VERSION 5.8 ;
BUSBITCHARS "[]" ;
DIVIDERCHAR "/" ;
UNITS
    DATABASE MICRONS 1000 ;
END UNITS

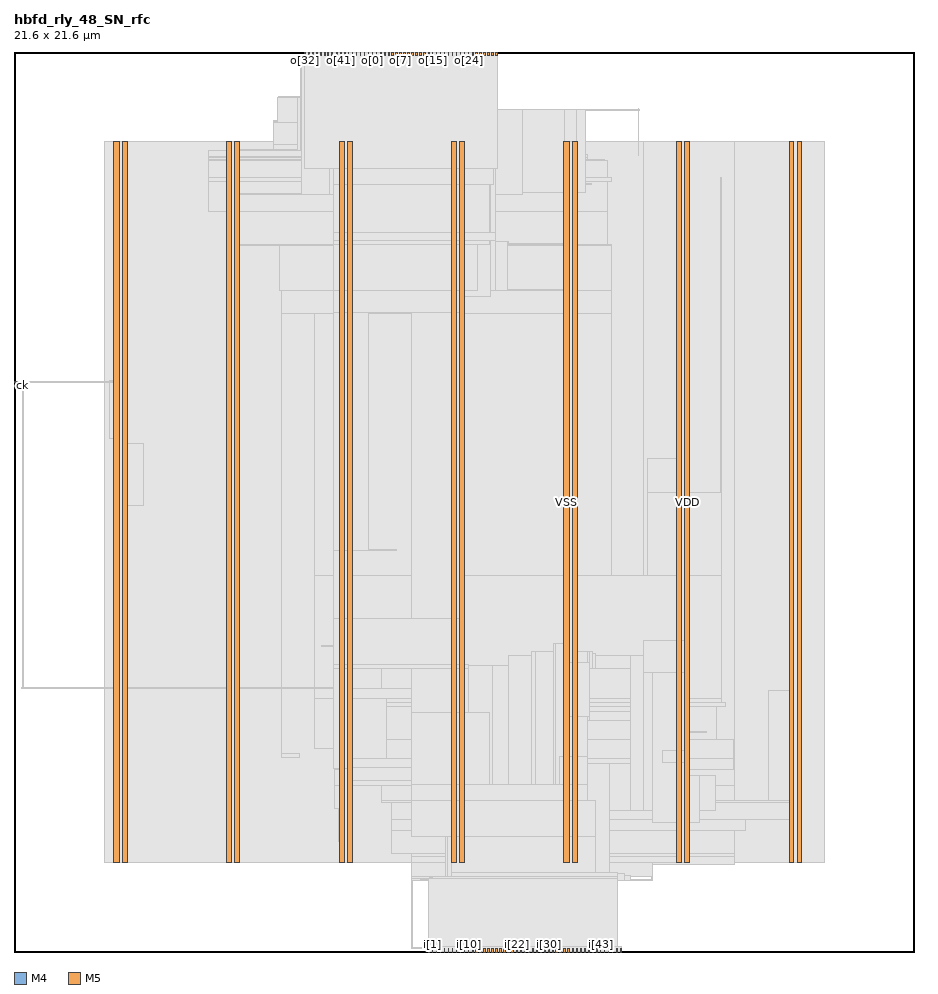
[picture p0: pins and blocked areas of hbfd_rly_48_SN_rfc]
MACRO hbfd_rly_48_SN_rfc
  FOREIGN hbfd_rly_48_SN_rfc 0 0 ;
  CLASS BLOCK ;
  SIZE 21.6 BY 21.6 ;
  PIN ck
    DIRECTION INPUT ;
    USE SIGNAL ;
    PORT
      LAYER M4 ;
        RECT  0 13.584 0.084 13.608 ;
    END
  END ck
  PIN i[0]
    DIRECTION INPUT ;
    USE SIGNAL ;
    PORT
      LAYER M5 ;
        RECT  9.936 0 9.96 0.084 ;
    END
  END i[0]
  PIN i[10]
    DIRECTION INPUT ;
    USE SIGNAL ;
    PORT
      LAYER M5 ;
        RECT  10.896 0 10.92 0.084 ;
    END
  END i[10]
  PIN i[11]
    DIRECTION INPUT ;
    USE SIGNAL ;
    PORT
      LAYER M5 ;
        RECT  10.992 0 11.016 0.084 ;
    END
  END i[11]
  PIN i[12]
    DIRECTION INPUT ;
    USE SIGNAL ;
    PORT
      LAYER M5 ;
        RECT  11.088 0 11.112 0.084 ;
    END
  END i[12]
  PIN i[13]
    DIRECTION INPUT ;
    USE SIGNAL ;
    PORT
      LAYER M5 ;
        RECT  11.184 0 11.208 0.084 ;
    END
  END i[13]
  PIN i[14]
    DIRECTION INPUT ;
    USE SIGNAL ;
    PORT
      LAYER M5 ;
        RECT  11.28 0 11.304 0.084 ;
    END
  END i[14]
  PIN i[15]
    DIRECTION INPUT ;
    USE SIGNAL ;
    PORT
      LAYER M5 ;
        RECT  11.376 0 11.4 0.084 ;
    END
  END i[15]
  PIN i[16]
    DIRECTION INPUT ;
    USE SIGNAL ;
    PORT
      LAYER M5 ;
        RECT  11.472 0 11.496 0.084 ;
    END
  END i[16]
  PIN i[17]
    DIRECTION INPUT ;
    USE SIGNAL ;
    PORT
      LAYER M5 ;
        RECT  11.568 0 11.592 0.084 ;
    END
  END i[17]
  PIN i[18]
    DIRECTION INPUT ;
    USE SIGNAL ;
    PORT
      LAYER M5 ;
        RECT  11.664 0 11.688 0.084 ;
    END
  END i[18]
  PIN i[19]
    DIRECTION INPUT ;
    USE SIGNAL ;
    PORT
      LAYER M5 ;
        RECT  11.76 0 11.784 0.084 ;
    END
  END i[19]
  PIN i[1]
    DIRECTION INPUT ;
    USE SIGNAL ;
    PORT
      LAYER M5 ;
        RECT  10.032 0 10.056 0.084 ;
    END
  END i[1]
  PIN i[20]
    DIRECTION INPUT ;
    USE SIGNAL ;
    PORT
      LAYER M5 ;
        RECT  11.856 0 11.88 0.084 ;
    END
  END i[20]
  PIN i[21]
    DIRECTION INPUT ;
    USE SIGNAL ;
    PORT
      LAYER M5 ;
        RECT  11.952 0 11.976 0.084 ;
    END
  END i[21]
  PIN i[22]
    DIRECTION INPUT ;
    USE SIGNAL ;
    PORT
      LAYER M5 ;
        RECT  12.048 0 12.072 0.084 ;
    END
  END i[22]
  PIN i[23]
    DIRECTION INPUT ;
    USE SIGNAL ;
    PORT
      LAYER M5 ;
        RECT  12.144 0 12.168 0.084 ;
    END
  END i[23]
  PIN i[24]
    DIRECTION INPUT ;
    USE SIGNAL ;
    PORT
      LAYER M5 ;
        RECT  12.24 0 12.264 0.084 ;
    END
  END i[24]
  PIN i[25]
    DIRECTION INPUT ;
    USE SIGNAL ;
    PORT
      LAYER M5 ;
        RECT  12.336 0 12.36 0.084 ;
    END
  END i[25]
  PIN i[26]
    DIRECTION INPUT ;
    USE SIGNAL ;
    PORT
      LAYER M5 ;
        RECT  12.432 0 12.456 0.084 ;
    END
  END i[26]
  PIN i[27]
    DIRECTION INPUT ;
    USE SIGNAL ;
    PORT
      LAYER M5 ;
        RECT  12.528 0 12.552 0.084 ;
    END
  END i[27]
  PIN i[28]
    DIRECTION INPUT ;
    USE SIGNAL ;
    PORT
      LAYER M5 ;
        RECT  12.624 0 12.648 0.084 ;
    END
  END i[28]
  PIN i[29]
    DIRECTION INPUT ;
    USE SIGNAL ;
    PORT
      LAYER M5 ;
        RECT  12.72 0 12.744 0.084 ;
    END
  END i[29]
  PIN i[2]
    DIRECTION INPUT ;
    USE SIGNAL ;
    PORT
      LAYER M5 ;
        RECT  10.128 0 10.152 0.084 ;
    END
  END i[2]
  PIN i[30]
    DIRECTION INPUT ;
    USE SIGNAL ;
    PORT
      LAYER M5 ;
        RECT  12.816 0 12.84 0.084 ;
    END
  END i[30]
  PIN i[31]
    DIRECTION INPUT ;
    USE SIGNAL ;
    PORT
      LAYER M5 ;
        RECT  12.912 0 12.936 0.084 ;
    END
  END i[31]
  PIN i[32]
    DIRECTION INPUT ;
    USE SIGNAL ;
    PORT
      LAYER M5 ;
        RECT  13.008 0 13.032 0.084 ;
    END
  END i[32]
  PIN i[33]
    DIRECTION INPUT ;
    USE SIGNAL ;
    PORT
      LAYER M5 ;
        RECT  13.104 0 13.128 0.084 ;
    END
  END i[33]
  PIN i[34]
    DIRECTION INPUT ;
    USE SIGNAL ;
    PORT
      LAYER M5 ;
        RECT  13.2 0 13.224 0.084 ;
    END
  END i[34]
  PIN i[35]
    DIRECTION INPUT ;
    USE SIGNAL ;
    PORT
      LAYER M5 ;
        RECT  13.296 0 13.32 0.084 ;
    END
  END i[35]
  PIN i[36]
    DIRECTION INPUT ;
    USE SIGNAL ;
    PORT
      LAYER M5 ;
        RECT  13.392 0 13.416 0.084 ;
    END
  END i[36]
  PIN i[37]
    DIRECTION INPUT ;
    USE SIGNAL ;
    PORT
      LAYER M5 ;
        RECT  13.488 0 13.512 0.084 ;
    END
  END i[37]
  PIN i[38]
    DIRECTION INPUT ;
    USE SIGNAL ;
    PORT
      LAYER M5 ;
        RECT  13.584 0 13.608 0.084 ;
    END
  END i[38]
  PIN i[39]
    DIRECTION INPUT ;
    USE SIGNAL ;
    PORT
      LAYER M5 ;
        RECT  13.68 0 13.704 0.084 ;
    END
  END i[39]
  PIN i[3]
    DIRECTION INPUT ;
    USE SIGNAL ;
    PORT
      LAYER M5 ;
        RECT  10.224 0 10.248 0.084 ;
    END
  END i[3]
  PIN i[40]
    DIRECTION INPUT ;
    USE SIGNAL ;
    PORT
      LAYER M5 ;
        RECT  13.776 0 13.8 0.084 ;
    END
  END i[40]
  PIN i[41]
    DIRECTION INPUT ;
    USE SIGNAL ;
    PORT
      LAYER M5 ;
        RECT  13.872 0 13.896 0.084 ;
    END
  END i[41]
  PIN i[42]
    DIRECTION INPUT ;
    USE SIGNAL ;
    PORT
      LAYER M5 ;
        RECT  13.968 0 13.992 0.084 ;
    END
  END i[42]
  PIN i[43]
    DIRECTION INPUT ;
    USE SIGNAL ;
    PORT
      LAYER M5 ;
        RECT  14.064 0 14.088 0.084 ;
    END
  END i[43]
  PIN i[44]
    DIRECTION INPUT ;
    USE SIGNAL ;
    PORT
      LAYER M5 ;
        RECT  14.16 0 14.184 0.084 ;
    END
  END i[44]
  PIN i[45]
    DIRECTION INPUT ;
    USE SIGNAL ;
    PORT
      LAYER M5 ;
        RECT  14.256 0 14.28 0.084 ;
    END
  END i[45]
  PIN i[46]
    DIRECTION INPUT ;
    USE SIGNAL ;
    PORT
      LAYER M5 ;
        RECT  14.352 0 14.376 0.084 ;
    END
  END i[46]
  PIN i[47]
    DIRECTION INPUT ;
    USE SIGNAL ;
    PORT
      LAYER M5 ;
        RECT  14.448 0 14.472 0.084 ;
    END
  END i[47]
  PIN i[4]
    DIRECTION INPUT ;
    USE SIGNAL ;
    PORT
      LAYER M5 ;
        RECT  10.32 0 10.344 0.084 ;
    END
  END i[4]
  PIN i[5]
    DIRECTION INPUT ;
    USE SIGNAL ;
    PORT
      LAYER M5 ;
        RECT  10.416 0 10.44 0.084 ;
    END
  END i[5]
  PIN i[6]
    DIRECTION INPUT ;
    USE SIGNAL ;
    PORT
      LAYER M5 ;
        RECT  10.512 0 10.536 0.084 ;
    END
  END i[6]
  PIN i[7]
    DIRECTION INPUT ;
    USE SIGNAL ;
    PORT
      LAYER M5 ;
        RECT  10.608 0 10.632 0.084 ;
    END
  END i[7]
  PIN i[8]
    DIRECTION INPUT ;
    USE SIGNAL ;
    PORT
      LAYER M5 ;
        RECT  10.704 0 10.728 0.084 ;
    END
  END i[8]
  PIN i[9]
    DIRECTION INPUT ;
    USE SIGNAL ;
    PORT
      LAYER M5 ;
        RECT  10.8 0 10.824 0.084 ;
    END
  END i[9]
  PIN o[0]
    DIRECTION OUTPUT ;
    USE SIGNAL ;
    PORT
      LAYER M5 ;
        RECT  8.592 21.516 8.616 21.6 ;
    END
  END o[0]
  PIN o[10]
    DIRECTION OUTPUT ;
    USE SIGNAL ;
    PORT
      LAYER M5 ;
        RECT  9.552 21.516 9.576 21.6 ;
    END
  END o[10]
  PIN o[11]
    DIRECTION OUTPUT ;
    USE SIGNAL ;
    PORT
      LAYER M5 ;
        RECT  9.648 21.516 9.672 21.6 ;
    END
  END o[11]
  PIN o[12]
    DIRECTION OUTPUT ;
    USE SIGNAL ;
    PORT
      LAYER M5 ;
        RECT  9.744 21.516 9.768 21.6 ;
    END
  END o[12]
  PIN o[13]
    DIRECTION OUTPUT ;
    USE SIGNAL ;
    PORT
      LAYER M5 ;
        RECT  9.84 21.516 9.864 21.6 ;
    END
  END o[13]
  PIN o[14]
    DIRECTION OUTPUT ;
    USE SIGNAL ;
    PORT
      LAYER M5 ;
        RECT  9.936 21.516 9.96 21.6 ;
    END
  END o[14]
  PIN o[15]
    DIRECTION OUTPUT ;
    USE SIGNAL ;
    PORT
      LAYER M5 ;
        RECT  10.032 21.516 10.056 21.6 ;
    END
  END o[15]
  PIN o[16]
    DIRECTION OUTPUT ;
    USE SIGNAL ;
    PORT
      LAYER M5 ;
        RECT  10.128 21.516 10.152 21.6 ;
    END
  END o[16]
  PIN o[17]
    DIRECTION OUTPUT ;
    USE SIGNAL ;
    PORT
      LAYER M5 ;
        RECT  10.224 21.516 10.248 21.6 ;
    END
  END o[17]
  PIN o[18]
    DIRECTION OUTPUT ;
    USE SIGNAL ;
    PORT
      LAYER M5 ;
        RECT  10.32 21.516 10.344 21.6 ;
    END
  END o[18]
  PIN o[19]
    DIRECTION OUTPUT ;
    USE SIGNAL ;
    PORT
      LAYER M5 ;
        RECT  10.416 21.516 10.44 21.6 ;
    END
  END o[19]
  PIN o[1]
    DIRECTION OUTPUT ;
    USE SIGNAL ;
    PORT
      LAYER M5 ;
        RECT  8.688 21.516 8.712 21.6 ;
    END
  END o[1]
  PIN o[20]
    DIRECTION OUTPUT ;
    USE SIGNAL ;
    PORT
      LAYER M5 ;
        RECT  10.512 21.516 10.536 21.6 ;
    END
  END o[20]
  PIN o[21]
    DIRECTION OUTPUT ;
    USE SIGNAL ;
    PORT
      LAYER M5 ;
        RECT  10.608 21.516 10.632 21.6 ;
    END
  END o[21]
  PIN o[22]
    DIRECTION OUTPUT ;
    USE SIGNAL ;
    PORT
      LAYER M5 ;
        RECT  10.704 21.516 10.728 21.6 ;
    END
  END o[22]
  PIN o[23]
    DIRECTION OUTPUT ;
    USE SIGNAL ;
    PORT
      LAYER M5 ;
        RECT  10.8 21.516 10.824 21.6 ;
    END
  END o[23]
  PIN o[24]
    DIRECTION OUTPUT ;
    USE SIGNAL ;
    PORT
      LAYER M5 ;
        RECT  10.896 21.516 10.92 21.6 ;
    END
  END o[24]
  PIN o[25]
    DIRECTION OUTPUT ;
    USE SIGNAL ;
    PORT
      LAYER M5 ;
        RECT  10.992 21.516 11.016 21.6 ;
    END
  END o[25]
  PIN o[26]
    DIRECTION OUTPUT ;
    USE SIGNAL ;
    PORT
      LAYER M5 ;
        RECT  11.088 21.516 11.112 21.6 ;
    END
  END o[26]
  PIN o[27]
    DIRECTION OUTPUT ;
    USE SIGNAL ;
    PORT
      LAYER M5 ;
        RECT  11.184 21.516 11.208 21.6 ;
    END
  END o[27]
  PIN o[28]
    DIRECTION OUTPUT ;
    USE SIGNAL ;
    PORT
      LAYER M5 ;
        RECT  11.28 21.516 11.304 21.6 ;
    END
  END o[28]
  PIN o[29]
    DIRECTION OUTPUT ;
    USE SIGNAL ;
    PORT
      LAYER M5 ;
        RECT  11.376 21.516 11.4 21.6 ;
    END
  END o[29]
  PIN o[2]
    DIRECTION OUTPUT ;
    USE SIGNAL ;
    PORT
      LAYER M5 ;
        RECT  8.784 21.516 8.808 21.6 ;
    END
  END o[2]
  PIN o[30]
    DIRECTION OUTPUT ;
    USE SIGNAL ;
    PORT
      LAYER M5 ;
        RECT  11.472 21.516 11.496 21.6 ;
    END
  END o[30]
  PIN o[31]
    DIRECTION OUTPUT ;
    USE SIGNAL ;
    PORT
      LAYER M5 ;
        RECT  11.568 21.516 11.592 21.6 ;
    END
  END o[31]
  PIN o[32]
    DIRECTION OUTPUT ;
    USE SIGNAL ;
    PORT
      LAYER M5 ;
        RECT  6.96 21.516 6.984 21.6 ;
    END
  END o[32]
  PIN o[33]
    DIRECTION OUTPUT ;
    USE SIGNAL ;
    PORT
      LAYER M5 ;
        RECT  7.056 21.516 7.08 21.6 ;
    END
  END o[33]
  PIN o[34]
    DIRECTION OUTPUT ;
    USE SIGNAL ;
    PORT
      LAYER M5 ;
        RECT  7.152 21.516 7.176 21.6 ;
    END
  END o[34]
  PIN o[35]
    DIRECTION OUTPUT ;
    USE SIGNAL ;
    PORT
      LAYER M5 ;
        RECT  7.248 21.516 7.272 21.6 ;
    END
  END o[35]
  PIN o[36]
    DIRECTION OUTPUT ;
    USE SIGNAL ;
    PORT
      LAYER M5 ;
        RECT  7.344 21.516 7.368 21.6 ;
    END
  END o[36]
  PIN o[37]
    DIRECTION OUTPUT ;
    USE SIGNAL ;
    PORT
      LAYER M5 ;
        RECT  7.44 21.516 7.464 21.6 ;
    END
  END o[37]
  PIN o[38]
    DIRECTION OUTPUT ;
    USE SIGNAL ;
    PORT
      LAYER M5 ;
        RECT  7.536 21.516 7.56 21.6 ;
    END
  END o[38]
  PIN o[39]
    DIRECTION OUTPUT ;
    USE SIGNAL ;
    PORT
      LAYER M5 ;
        RECT  7.632 21.516 7.656 21.6 ;
    END
  END o[39]
  PIN o[3]
    DIRECTION OUTPUT ;
    USE SIGNAL ;
    PORT
      LAYER M5 ;
        RECT  8.88 21.516 8.904 21.6 ;
    END
  END o[3]
  PIN o[40]
    DIRECTION OUTPUT ;
    USE SIGNAL ;
    PORT
      LAYER M5 ;
        RECT  7.728 21.516 7.752 21.6 ;
    END
  END o[40]
  PIN o[41]
    DIRECTION OUTPUT ;
    USE SIGNAL ;
    PORT
      LAYER M5 ;
        RECT  7.824 21.516 7.848 21.6 ;
    END
  END o[41]
  PIN o[42]
    DIRECTION OUTPUT ;
    USE SIGNAL ;
    PORT
      LAYER M5 ;
        RECT  7.92 21.516 7.944 21.6 ;
    END
  END o[42]
  PIN o[43]
    DIRECTION OUTPUT ;
    USE SIGNAL ;
    PORT
      LAYER M5 ;
        RECT  8.016 21.516 8.04 21.6 ;
    END
  END o[43]
  PIN o[44]
    DIRECTION OUTPUT ;
    USE SIGNAL ;
    PORT
      LAYER M5 ;
        RECT  8.112 21.516 8.136 21.6 ;
    END
  END o[44]
  PIN o[45]
    DIRECTION OUTPUT ;
    USE SIGNAL ;
    PORT
      LAYER M5 ;
        RECT  8.208 21.516 8.232 21.6 ;
    END
  END o[45]
  PIN o[46]
    DIRECTION OUTPUT ;
    USE SIGNAL ;
    PORT
      LAYER M5 ;
        RECT  8.304 21.516 8.328 21.6 ;
    END
  END o[46]
  PIN o[47]
    DIRECTION OUTPUT ;
    USE SIGNAL ;
    PORT
      LAYER M5 ;
        RECT  8.4 21.516 8.424 21.6 ;
    END
  END o[47]
  PIN o[4]
    DIRECTION OUTPUT ;
    USE SIGNAL ;
    PORT
      LAYER M5 ;
        RECT  8.976 21.516 9 21.6 ;
    END
  END o[4]
  PIN o[5]
    DIRECTION OUTPUT ;
    USE SIGNAL ;
    PORT
      LAYER M5 ;
        RECT  9.072 21.516 9.096 21.6 ;
    END
  END o[5]
  PIN o[6]
    DIRECTION OUTPUT ;
    USE SIGNAL ;
    PORT
      LAYER M5 ;
        RECT  9.168 21.516 9.192 21.6 ;
    END
  END o[6]
  PIN o[7]
    DIRECTION OUTPUT ;
    USE SIGNAL ;
    PORT
      LAYER M5 ;
        RECT  9.264 21.516 9.288 21.6 ;
    END
  END o[7]
  PIN o[8]
    DIRECTION OUTPUT ;
    USE SIGNAL ;
    PORT
      LAYER M5 ;
        RECT  9.36 21.516 9.384 21.6 ;
    END
  END o[8]
  PIN o[9]
    DIRECTION OUTPUT ;
    USE SIGNAL ;
    PORT
      LAYER M5 ;
        RECT  9.456 21.516 9.48 21.6 ;
    END
  END o[9]
  PIN rfi
    DIRECTION INPUT ;
    USE SIGNAL ;
    PORT
      LAYER M5 ;
        RECT  14.544 0 14.568 0.084 ;
    END
  END rfi
  PIN rfo
    DIRECTION OUTPUT ;
    USE SIGNAL ;
    PORT
      LAYER M5 ;
        RECT  8.496 21.516 8.52 21.6 ;
    END
  END rfo
  PIN rs
    DIRECTION INPUT ;
    USE SIGNAL ;
    PORT
      LAYER M4 ;
        RECT  0 13.68 0.084 13.704 ;
    END
  END rs
  PIN VDD
    DIRECTION INOUT ;
    USE POWER ;
    PORT
      LAYER M5 ;
        RECT  18.792 2.151 18.912 19.449 ;
        RECT  16.092 2.151 16.212 19.449 ;
        RECT  13.392 2.151 13.512 19.449 ;
        RECT  10.692 2.151 10.812 19.449 ;
        RECT  7.992 2.151 8.112 19.449 ;
        RECT  5.292 2.151 5.412 19.449 ;
        RECT  2.592 2.151 2.712 19.449 ;
    END
  END VDD
  PIN VSS
    DIRECTION INOUT ;
    USE GROUND ;
    PORT
      LAYER M5 ;
        RECT  18.6 2.137 18.72 19.463 ;
        RECT  15.9 2.137 16.02 19.463 ;
        RECT  13.2 2.137 13.32 19.463 ;
        RECT  10.5 2.137 10.62 19.463 ;
        RECT  7.8 2.137 7.92 19.463 ;
        RECT  5.1 2.137 5.22 19.463 ;
        RECT  2.4 2.137 2.52 19.463 ;
    END
  END VSS
  OBS
    LAYER RVTN ;
     RECT  2.16 2.16 19.44 2.295 ;
     RECT  2.16 2.565 19.44 2.835 ;
     RECT  2.16 3.105 19.44 3.375 ;
     RECT  2.16 3.645 19.44 3.915 ;
     RECT  2.16 4.185 19.44 4.455 ;
     RECT  2.16 4.725 19.44 4.995 ;
     RECT  2.16 5.265 19.44 5.535 ;
     RECT  2.16 5.805 19.44 6.075 ;
     RECT  2.16 6.345 19.44 6.615 ;
     RECT  2.16 6.885 19.44 7.155 ;
     RECT  2.16 7.425 19.44 7.695 ;
     RECT  2.16 7.965 19.44 8.235 ;
     RECT  2.16 8.505 19.44 8.775 ;
     RECT  2.16 9.045 19.44 9.315 ;
     RECT  2.16 9.585 19.44 9.855 ;
     RECT  2.16 10.125 19.44 10.395 ;
     RECT  2.16 10.665 19.44 10.935 ;
     RECT  2.16 11.205 19.44 11.475 ;
     RECT  2.16 11.745 19.44 12.015 ;
     RECT  2.16 12.285 19.44 12.555 ;
     RECT  2.16 12.825 19.44 13.095 ;
     RECT  2.16 13.365 19.44 13.635 ;
     RECT  2.16 13.905 19.44 14.175 ;
     RECT  2.16 14.445 19.44 14.715 ;
     RECT  2.16 14.985 19.44 15.255 ;
     RECT  2.16 15.525 19.44 15.795 ;
     RECT  2.16 16.065 19.44 16.335 ;
     RECT  2.16 16.605 19.44 16.875 ;
     RECT  2.16 17.145 19.44 17.415 ;
     RECT  2.16 17.685 19.44 17.955 ;
     RECT  2.16 18.225 19.44 18.495 ;
     RECT  2.16 18.765 19.44 19.035 ;
     RECT  2.16 19.305 19.44 19.44 ;
    LAYER RVTP ;
     RECT  2.16 2.295 19.44 2.565 ;
     RECT  2.16 2.835 19.44 3.105 ;
     RECT  2.16 3.375 19.44 3.645 ;
     RECT  2.16 3.915 19.44 4.185 ;
     RECT  2.16 4.455 19.44 4.725 ;
     RECT  2.16 4.995 19.44 5.265 ;
     RECT  2.16 5.535 19.44 5.805 ;
     RECT  2.16 6.075 19.44 6.345 ;
     RECT  2.16 6.615 19.44 6.885 ;
     RECT  2.16 7.155 19.44 7.425 ;
     RECT  2.16 7.695 19.44 7.965 ;
     RECT  2.16 8.235 19.44 8.505 ;
     RECT  2.16 8.775 19.44 9.045 ;
     RECT  2.16 9.315 19.44 9.585 ;
     RECT  2.16 9.855 19.44 10.125 ;
     RECT  2.16 10.395 19.44 10.665 ;
     RECT  2.16 10.935 19.44 11.205 ;
     RECT  2.16 11.475 19.44 11.745 ;
     RECT  2.16 12.015 19.44 12.285 ;
     RECT  2.16 12.555 19.44 12.825 ;
     RECT  2.16 13.095 19.44 13.365 ;
     RECT  2.16 13.635 19.44 13.905 ;
     RECT  2.16 14.175 19.44 14.445 ;
     RECT  2.16 14.715 19.44 14.985 ;
     RECT  2.16 15.255 19.44 15.525 ;
     RECT  2.16 15.795 19.44 16.065 ;
     RECT  2.16 16.335 19.44 16.605 ;
     RECT  2.16 16.875 19.44 17.145 ;
     RECT  2.16 17.415 19.44 17.685 ;
     RECT  2.16 17.955 19.44 18.225 ;
     RECT  2.16 18.495 19.44 18.765 ;
     RECT  2.16 19.035 19.44 19.305 ;
    LAYER M1 ;
     RECT  2.16 2.151 19.44 19.449 ;
    LAYER M2 ;
     RECT  2.16 2.151 9.571 19.449 ;
     RECT  9.571 2.106 10.723 19.449 ;
     RECT  10.723 2.07 12.011 19.449 ;
     RECT  12.011 2.106 12.991 19.449 ;
     RECT  12.991 2.07 15.107 19.449 ;
     RECT  15.107 2.106 17.303 19.449 ;
     RECT  17.303 2.151 19.44 19.449 ;
    LAYER M3 ;
     RECT  9.54 0.091 9.558 1.723 ;
     RECT  10.296 0.091 10.314 1.723 ;
     RECT  11.556 0.091 11.574 1.723 ;
     RECT  14.256 0.091 14.274 1.723 ;
     RECT  9.54 1.723 14.274 1.771 ;
     RECT  9.54 1.771 14.526 1.819 ;
     RECT  15.3 1.723 15.318 1.819 ;
     RECT  9.54 1.819 15.318 2.143 ;
     RECT  9.54 2.143 16.005 2.299 ;
     RECT  17.28 2.101 17.298 2.299 ;
     RECT  9.54 2.299 17.298 2.371 ;
     RECT  2.415 2.143 2.505 2.413 ;
     RECT  5.115 2.143 5.205 2.413 ;
     RECT  7.815 2.143 7.905 2.413 ;
     RECT  18.615 2.143 18.705 2.413 ;
     RECT  7.815 2.413 8.097 2.641 ;
     RECT  9.072 2.371 17.298 2.911 ;
     RECT  9.072 2.911 17.55 3.181 ;
     RECT  18.615 2.413 18.897 3.181 ;
     RECT  7.776 2.641 8.097 3.451 ;
     RECT  9.072 3.181 18.897 3.577 ;
     RECT  8.82 3.577 18.897 3.641 ;
     RECT  7.704 3.451 8.097 3.991 ;
     RECT  8.82 3.641 17.298 3.991 ;
     RECT  7.704 3.991 17.298 4.379 ;
     RECT  7.704 4.379 17.262 4.649 ;
     RECT  6.408 4.657 6.858 4.757 ;
     RECT  7.704 4.649 8.097 4.891 ;
     RECT  8.928 4.649 17.262 5.099 ;
     RECT  8.928 5.099 16.866 5.881 ;
     RECT  8.928 5.881 17.082 5.999 ;
     RECT  7.2 4.891 8.097 6.079 ;
     RECT  8.928 5.999 16.974 6.079 ;
     RECT  18.108 3.641 18.897 6.269 ;
     RECT  7.2 6.079 16.974 9.041 ;
     RECT  2.415 2.413 2.697 10.705 ;
     RECT  15.192 9.041 16.974 11.039 ;
     RECT  15.192 11.039 16.197 11.849 ;
     RECT  2.415 10.705 3.114 12.209 ;
     RECT  2.415 12.209 2.697 12.325 ;
     RECT  2.304 12.325 2.697 13.709 ;
     RECT  6.408 4.757 6.426 15.331 ;
     RECT  7.2 9.041 14.346 15.331 ;
     RECT  6.408 15.331 14.346 15.871 ;
     RECT  5.115 2.413 5.397 16.951 ;
     RECT  6.372 15.871 14.346 16.951 ;
     RECT  5.115 16.951 14.346 16.979 ;
     RECT  5.115 16.979 14.238 17.761 ;
     RECT  4.68 17.761 14.238 18.499 ;
     RECT  4.68 18.499 14.346 18.599 ;
     RECT  16.956 11.039 16.974 18.599 ;
     RECT  4.68 18.599 14.238 18.995 ;
     RECT  4.68 18.995 14.166 19.031 ;
     RECT  4.68 19.031 13.77 19.067 ;
     RECT  4.68 19.067 11.358 19.103 ;
     RECT  12.204 19.067 13.77 19.139 ;
     RECT  2.415 13.709 2.697 19.187 ;
     RECT  15.915 11.849 16.197 19.187 ;
     RECT  18.615 6.269 18.897 19.187 ;
     RECT  4.68 19.103 11.07 19.229 ;
     RECT  5.115 19.229 8.442 19.265 ;
     RECT  10.476 19.229 11.034 19.301 ;
     RECT  12.276 19.139 13.698 19.325 ;
     RECT  6.228 19.265 8.442 19.373 ;
     RECT  12.276 19.325 13.305 19.373 ;
     RECT  2.415 19.187 2.505 19.457 ;
     RECT  5.115 19.265 5.205 19.457 ;
     RECT  13.215 19.373 13.305 19.457 ;
     RECT  15.915 19.187 16.005 19.457 ;
     RECT  18.615 19.187 18.705 19.457 ;
     RECT  10.476 19.301 10.746 19.565 ;
     RECT  10.476 19.565 10.494 19.613 ;
     RECT  6.228 19.373 8.406 19.949 ;
     RECT  6.336 19.949 8.334 20.045 ;
     RECT  14.976 19.111 14.994 20.237 ;
     RECT  6.336 20.045 6.894 20.525 ;
     RECT  7.632 20.045 8.334 20.525 ;
     RECT  7.632 20.525 7.65 20.573 ;
     RECT  6.876 20.525 6.894 21.485 ;
    LAYER M4 ;
     RECT  0.06 13.584 0.227 13.704 ;
     RECT  0.181 6.336 2.408 6.36 ;
     RECT  0.227 13.68 2.408 13.704 ;
     RECT  2.408 2.148 2.512 19.452 ;
     RECT  2.512 2.418 2.704 19.182 ;
     RECT  2.704 6.336 5.108 6.36 ;
     RECT  5.108 2.148 5.212 19.452 ;
     RECT  5.212 2.418 5.404 19.182 ;
     RECT  6.217 19.92 6.325 19.944 ;
     RECT  6.325 19.92 6.793 20.52 ;
     RECT  6.793 19.248 6.865 20.52 ;
     RECT  5.404 18.192 6.908 18.216 ;
     RECT  6.865 19.248 6.908 21.48 ;
     RECT  6.908 18.192 7.571 21.48 ;
     RECT  7.669 4.416 7.808 4.44 ;
     RECT  5.404 6.336 7.808 6.36 ;
     RECT  7.369 7.344 7.808 7.368 ;
     RECT  7.571 18.192 7.808 20.568 ;
     RECT  7.808 2.148 7.912 20.568 ;
     RECT  7.912 2.418 8.104 20.568 ;
     RECT  8.104 17.664 8.147 20.568 ;
     RECT  8.147 17.664 8.345 20.52 ;
     RECT  8.345 17.664 8.417 19.944 ;
     RECT  8.417 17.664 8.453 19.368 ;
     RECT  8.104 6.336 8.819 7.992 ;
     RECT  8.104 15.36 9.157 16.536 ;
     RECT  8.453 17.664 9.157 18.84 ;
     RECT  8.104 9.648 9.173 9.672 ;
     RECT  8.819 7.968 9.245 7.992 ;
     RECT  9.157 15.36 9.829 18.84 ;
     RECT  8.104 4.128 9.889 4.44 ;
     RECT  9.745 1.728 9.97 1.752 ;
     RECT  9.541 2.784 10.069 2.808 ;
     RECT  9.889 4.128 10.069 4.968 ;
     RECT  8.819 6.336 10.277 6.84 ;
     RECT  10.277 6.336 10.316 6.936 ;
     RECT  9.829 14.544 10.316 18.84 ;
     RECT  10.069 2.784 10.321 4.968 ;
     RECT  10.316 6.336 10.321 7.032 ;
     RECT  9.97 1.728 10.357 1.8 ;
     RECT  10.321 2.784 10.357 5.016 ;
     RECT  10.316 14.544 10.357 18.936 ;
     RECT  9.529 0.096 10.369 0.12 ;
     RECT  10.357 1.728 10.393 5.016 ;
     RECT  10.321 6 10.393 7.032 ;
     RECT  10.357 14.544 10.405 19.656 ;
     RECT  10.393 1.728 10.508 7.032 ;
     RECT  10.405 14.544 10.508 20.232 ;
     RECT  10.261 21.408 10.547 21.432 ;
     RECT  10.508 1.728 10.804 20.232 ;
     RECT  10.804 1.728 10.835 6.888 ;
     RECT  10.804 15.744 11.441 20.232 ;
     RECT  10.835 2.88 11.477 6.888 ;
     RECT  11.441 15.888 11.555 20.232 ;
     RECT  11.545 0.096 11.629 0.12 ;
     RECT  10.835 1.728 11.809 1.848 ;
     RECT  11.555 15.888 11.837 17.064 ;
     RECT  11.477 3.984 11.869 6.888 ;
     RECT  11.837 16.992 11.873 17.064 ;
     RECT  11.477 2.88 11.989 2.904 ;
     RECT  11.555 18.192 12.197 20.232 ;
     RECT  11.869 3.984 12.409 7.128 ;
     RECT  12.409 3.984 12.517 7.224 ;
     RECT  11.809 1.728 12.869 1.8 ;
     RECT  12.517 3.408 12.949 7.224 ;
     RECT  12.949 3.408 12.997 7.416 ;
     RECT  12.869 1.728 13.208 1.896 ;
     RECT  12.997 2.88 13.208 7.416 ;
     RECT  11.837 15.888 13.208 15.912 ;
     RECT  11.873 16.992 13.208 17.016 ;
     RECT  12.197 18.24 13.208 20.232 ;
     RECT  13.285 0.336 13.381 0.36 ;
     RECT  13.381 0.24 13.429 0.36 ;
     RECT  13.208 1.728 13.504 20.232 ;
     RECT  13.429 0.144 13.619 0.36 ;
     RECT  13.619 0.144 13.667 0.264 ;
     RECT  13.504 18.24 13.709 20.232 ;
     RECT  13.504 1.728 13.763 7.224 ;
     RECT  13.763 5.568 13.811 7.224 ;
     RECT  13.709 18.432 13.853 18.456 ;
     RECT  13.811 6.816 13.889 7.224 ;
     RECT  13.889 6.816 13.961 7.176 ;
     RECT  13.763 1.728 14.285 4.536 ;
     RECT  14.245 0.096 14.579 0.12 ;
     RECT  14.285 1.728 14.645 1.896 ;
     RECT  14.285 3.408 14.785 4.536 ;
     RECT  13.811 5.568 14.785 5.784 ;
     RECT  13.961 6.816 14.785 7.128 ;
     RECT  14.645 1.728 14.789 1.848 ;
     RECT  13.709 20.208 15.005 20.232 ;
     RECT  14.785 3.408 15.101 7.128 ;
     RECT  15.101 3.408 15.325 7.464 ;
     RECT  14.789 1.728 15.329 1.752 ;
     RECT  15.325 3.12 15.908 7.464 ;
     RECT  15.908 2.148 16.012 19.452 ;
     RECT  16.012 2.418 16.204 19.182 ;
     RECT  16.204 3.12 16.445 4.248 ;
     RECT  16.204 5.28 16.625 5.304 ;
     RECT  16.445 3.408 16.841 4.248 ;
     RECT  18.608 2.148 18.712 19.452 ;
     RECT  18.712 2.418 18.904 19.182 ;
    LAYER M5 ;
     RECT  9.936 0.016 14.568 0.131 ;
     RECT  9.936 0.131 14.472 1.763 ;
     RECT  10.032 1.763 14.472 1.811 ;
     RECT  10.5 1.811 14.472 1.907 ;
     RECT  2.4 2.137 2.52 2.151 ;
     RECT  5.1 2.137 5.22 2.151 ;
     RECT  7.8 2.137 7.92 2.151 ;
     RECT  15.9 2.137 16.02 2.151 ;
     RECT  18.6 2.137 18.72 2.151 ;
     RECT  10.5 1.907 13.944 2.773 ;
     RECT  9.552 2.773 13.944 3.635 ;
     RECT  9.552 3.635 13.752 4.019 ;
     RECT  7.8 2.151 8.112 4.405 ;
     RECT  15.9 2.151 16.212 4.549 ;
     RECT  13.104 4.019 13.752 4.691 ;
     RECT  15.552 4.549 16.212 4.835 ;
     RECT  13.2 4.691 13.752 5.653 ;
     RECT  9.552 4.019 11.4 5.747 ;
     RECT  15.9 4.835 16.212 6.709 ;
     RECT  7.68 4.405 8.112 6.805 ;
     RECT  9.552 5.747 10.92 6.805 ;
     RECT  7.68 6.805 10.92 6.899 ;
     RECT  13.2 5.653 13.8 6.947 ;
     RECT  15.12 6.709 16.212 7.475 ;
     RECT  7.68 6.899 10.812 8.003 ;
     RECT  7.68 8.003 8.112 9.637 ;
     RECT  0.192 6.325 0.216 13.619 ;
     RECT  7.68 9.637 8.52 15.349 ;
     RECT  9.552 8.003 10.812 15.349 ;
     RECT  7.68 15.349 10.812 15.877 ;
     RECT  7.68 15.877 11.112 16.981 ;
     RECT  7.68 16.981 11.4 17.077 ;
     RECT  7.68 17.077 11.544 17.267 ;
     RECT  7.68 17.267 11.4 18.421 ;
     RECT  7.68 18.421 11.496 18.805 ;
     RECT  2.4 2.151 2.712 19.449 ;
     RECT  5.1 2.151 5.412 19.449 ;
     RECT  13.2 6.947 13.512 19.449 ;
     RECT  15.9 7.475 16.212 19.449 ;
     RECT  18.6 2.151 18.912 19.449 ;
     RECT  2.4 19.449 2.52 19.463 ;
     RECT  5.1 19.449 5.22 19.463 ;
     RECT  13.2 19.449 13.32 19.463 ;
     RECT  15.9 19.449 16.02 19.463 ;
     RECT  18.6 19.449 18.72 19.463 ;
     RECT  6.96 18.805 11.592 21.584 ;
  END
END hbfd_rly_48_SN_rfc
END LIBRARY
